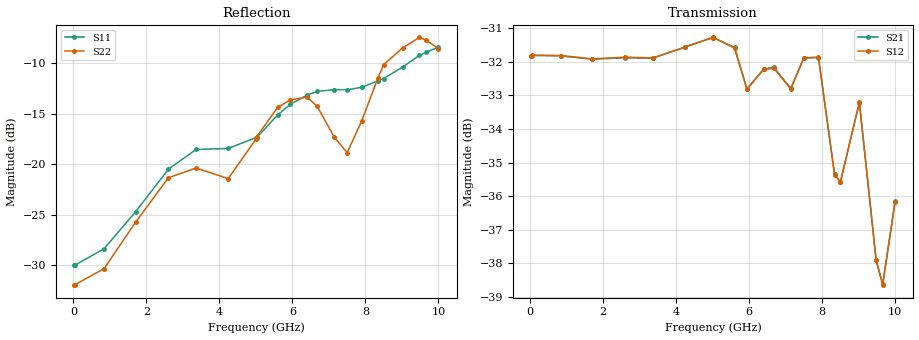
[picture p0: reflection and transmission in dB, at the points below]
! Integrated Device Technology
! Corporate Headquarters
! 6024 Silver Creek Valley Road
! San Jose, CA 95138  USA
! Phone:  1-408-284-8200
! Toll Free:  1-800-223-1366
! Webpage:  http://www.idt.com/
! Timing and RF Division
! 515 Groton Road, Suite 102
! Westford, MA 01886-6024
! Device:  F1958
! Description: 7-bit 0.25 dB Digital Step Attenuator
! Frequency:  0.001 -  6.000 GHz
! Package:  4x4 mm Thin QFN Plastic Package: 24 pin
! Ports:  2 RF, 12 DC
!  Pin  1  = D0
!  Pin  2  = VDD
!  Pin  3  = VMODE
!  Pin  4  = GND
!  Pin  5  = RF1  =  Port 1
!  Pin  6  = GND
!  Pin  7  = GND
!  Pin  8  = GND
!  Pin  9  = GND
!  Pin 10  = GND
!  Pin 11  = GND
!  Pin 12  = GND
!  Pin 13  = GND
!  Pin 14  = RF2  =  Port 2
!  Pin 15  = GND
!  Pin 16  = LE
!  Pin 17  = CLK
!  Pin 18  = DATA
!  Pin 19  = D6
!  Pin 20  = D5
!  Pin 21  = D4
!  Pin 22  = D3
!  Pin 23  = D2
!  Pin 24  = D1
! State:  124
! Atten State:  31.00 dB
! Voltage:  +3.30 Volts
! Current:  0.259 mA
! Data:  The device was measured on a F1958 evaluation board which has
!  individual transmission lines to the RF pins.  Data was collected
!  using a calibrated network analyzer.  The evaluation board was
!  de-embedded using Automatic Fixture Removal (AFR).
!  The reference plane is the edge of the package pin.
! Misc:
!  Action Tracker AT0419
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# GHz S dB R 50
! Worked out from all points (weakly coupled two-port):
!   500 points, 20 MHz to 10 GHz, reference 50 ohm
!   highest |S21| = -31.27 dB at 5 GHz (marker M1); lowest = -38.6 dB at 9.66 GHz (marker M2)
!   lowest |S11| = -30.0 dB at 40 MHz (marker M3), VSWR 1.07, Z = 46.9 - j0.0453 ohm
!   |S11| at or under -10 dB: start of sweep to 9.126 GHz
!   |S22| runs from -32.2 to -7.4 dB; largest |S21 - S12| = 0.00021
!   S11 on the Smith chart (normalised r, x): 20 MHz: 0.94, -0.00; 6.4 GHz: 0.67, +0.17; 10 GHz: 0.67, +0.59
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0.02  -29.98 -178.9  -31.82 -0.1  -31.82 -0.1  -31.99 -178.9
0.04  -30.01 -179.1  -31.81 -0.3  -31.80 -0.2  -31.95 -178.4
0.84  -28.38 171.3  -31.82 -8.7  -31.81 -8.7  -30.35 172.9
1.7  -24.72 171.3  -31.92 -17.3  -31.91 -17.2  -25.76 171.8
2.6  -20.49 176.9  -31.88 -26.4  -31.86 -26.4  -21.34 179.7
3.36  -18.53 -175.7  -31.89 -34.8  -31.88 -34.9  -20.37 -169.3
4.24  -18.43 -179.2  -31.56 -44.0  -31.56 -44.1  -21.42 169.1
5  -17.35 161.5  -31.27 -53.5  -31.28 -53.6  -17.50 137.5
5.02  -17.36 160.7  -31.28 -53.9  -31.27 -53.9  -17.26 138.5
5.6  -15.08 150.7  -31.57 -62.6  -31.59 -62.5  -14.34 140.2
5.94  -14.06 148.3  -32.80 -65.9  -32.82 -65.9  -13.62 148.6
6.4  -13.13 147.7  -32.21 -71.3  -32.22 -71.2  -13.33 155.5
6.68  -12.77 146.6  -32.16 -73.8  -32.19 -73.7  -14.26 157.4
7.14  -12.59 142.7  -32.79 -78.9  -32.81 -78.7  -17.28 151.5
7.5  -12.61 138.1  -31.88 -82.3  -31.88 -82.2  -18.85 119.7
7.9  -12.36 128.8  -31.87 -98.9  -31.86 -99.0  -15.67 89.3
8.34  -11.72 118.8  -35.34 -104.2  -35.37 -104.5  -11.47 84.1
8.5  -11.49 115.4  -35.59 -95.5  -35.57 -95.7  -10.11 87.7
9.02  -10.35 107.7  -33.21 -104.5  -33.20 -104.9  -8.45 97.8
9.48  -9.19 101.8  -37.91 -110.1  -37.90 -109.6  -7.41 107.6
9.66  -8.89 100.6  -38.62 -96.4  -38.65 -95.6  -7.67 110.2
10  -8.38 99.7  -36.15 -80.5  -36.16 -80.3  -8.52 113.8
